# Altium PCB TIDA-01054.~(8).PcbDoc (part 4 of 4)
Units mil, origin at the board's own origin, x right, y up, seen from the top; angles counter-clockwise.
Board outline 4448 x 3930 mil, 4 copper layers (Layer 1 - Top Layer, Layer 2 - GND, Layer 3 - PWR, Layer 4 - Bottom Layer), stack 59.034 mil thick; 538 components, 285 nets, 1542 pads, 769 vias.

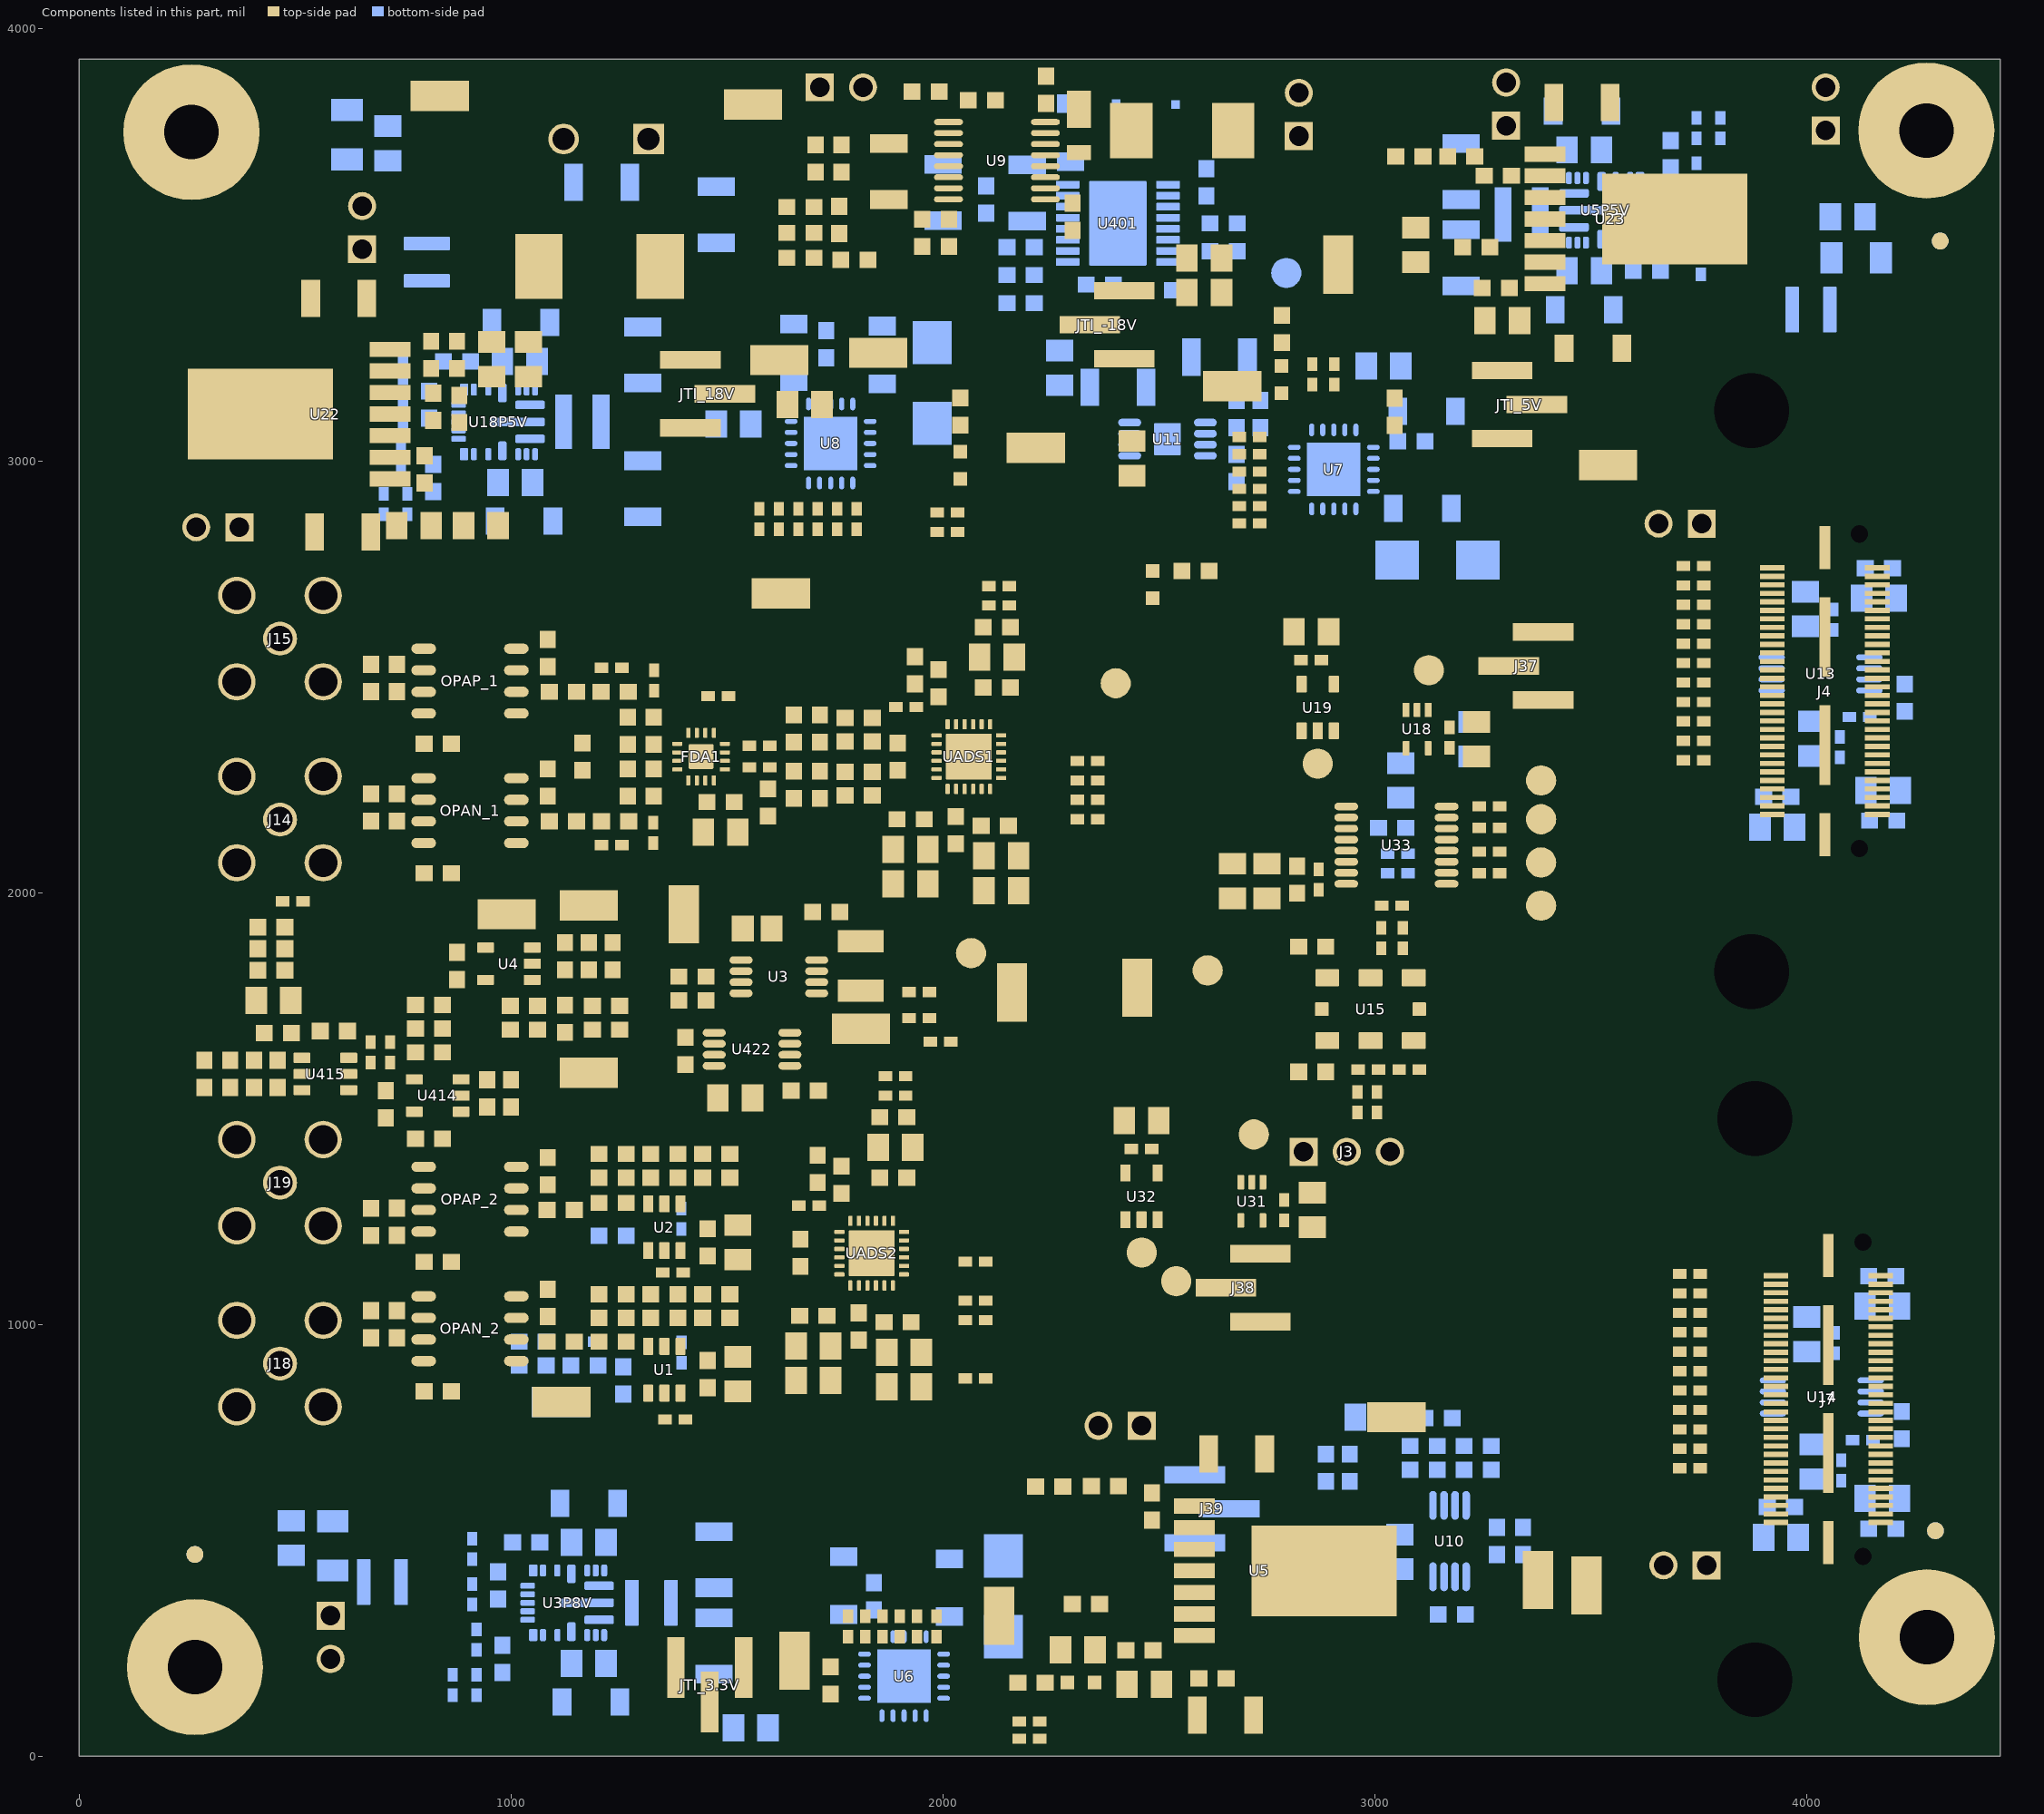
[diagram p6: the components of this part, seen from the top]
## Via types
v1: diameter 20, hole 10, Layer 1 - Top Layer to Layer 4 - Bottom Layer, tented both sides, 381 vias
v2: diameter 20, hole 10, Layer 1 - Top Layer to Layer 4 - Bottom Layer, 258 vias
v3: diameter 20, hole 10, Layer 1 - Top Layer to Layer 4 - Bottom Layer, tented bottom, 57 vias
v4: diameter 19.68, hole 7.87, Layer 1 - Top Layer to Layer 4 - Bottom Layer, tented both sides, 48 vias
v5: diameter 20, hole 10, Layer 1 - Top Layer to Layer 4 - Bottom Layer, tented top, 19 vias
v6: diameter 19.68, hole 7.87, Layer 1 - Top Layer to Layer 4 - Bottom Layer, 6 vias

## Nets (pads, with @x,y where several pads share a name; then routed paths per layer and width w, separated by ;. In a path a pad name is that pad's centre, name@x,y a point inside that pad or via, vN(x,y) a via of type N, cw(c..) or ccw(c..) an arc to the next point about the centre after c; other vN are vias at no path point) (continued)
pads on no net: FID1.1 FID2.1 FID3.1 FID4.1 FID5.1 FID6.1 H1.1 H2.1 H3.1 H4.1 H9. H11. H13. H15. J4.2 J4.3 J4.4 J4.5 J4.6 J4.7 J4.8 J4.9 J4.10 J4.11 J4.12 J4.13 J4.14 J4.15 J4.17 J4.19 J4.21 J4.23 J4.25 J4.26 J4.27 J4.29 J4.31 J4.33 J4.35 J4.36 J4.37 J4.39 J4.41 J4.43 J4.45 J4.46 J4.47 J4.48 J4.49 J4.51 J4.52 J4.53 J4.54 J4.55 J4.57 J4.MH1 J4.MH2 J7.2 J7.3 J7.4 J7.5 J7.6 J7.7 J7.8 J7.9 J7.10 J7.11 J7.12 J7.13 J7.14 J7.15 J7.17 J7.19 J7.21 J7.23 J7.25 J7.26 J7.27 J7.29 J7.31 J7.33 J7.35 J7.36 J7.37 J7.39 J7.41 J7.43 J7.45 J7.46 J7.47 J7.48 J7.49 J7.51 J7.52 J7.53 J7.54 J7.55 J7.57 J7.MH1 J7.MH2 OPAN_1.1 OPAN_1.5 OPAN_1.8 OPAN_2.1 OPAN_2.5 OPAN_2.8 OPAP_1.1 OPAP_1.5 OPAP_1.8 OPAP_2.1 OPAP_2.5 OPAP_2.8 U3P8V.3 U3P8V.4A U3P8V.4B U3P8V.8A U3P8V.8B U3P8V.9A U3P8V.9B U3P8V.9C U3P8V.9D U3P8V.10A U3P8V.10B U3P8V.14A U3P8V.14B U5P5V.3 U5P5V.4A U5P5V.4B U5P5V.8A U5P5V.8B U5P5V.9A U5P5V.9B U5P5V.9C U5P5V.9D U5P5V.10A U5P5V.10B U5P5V.14A U5P5V.14B U9.2 U9.4 U11.3 U11.7 U15.1@2874.25,1656.91 U15.1@2905.75,1656.91 U15.2@2974.25,1656.91 U15.2@3005.75,1656.91 U15.3@3074.25,1656.91 U15.3@3105.75,1656.91 U15.4@3074.25,1802.58 U15.4@3105.75,1802.58 U15.5@2974.25,1802.58 U15.5@3005.75,1802.58 U15.6@2874.25,1802.58 U15.6@2905.75,1802.58 U18P5V.3 U18P5V.4A U18P5V.4B U18P5V.8A U18P5V.8B U18P5V.9A U18P5V.9B U18P5V.9C U18P5V.9D U18P5V.10A U18P5V.10B U18P5V.14A U18P5V.14B U19.1 U32.1 U33.8 U401.17@2405,3550 U422.1 U422.3 U422.5 U422.7 U422.8 UADS1.6 UADS2.6

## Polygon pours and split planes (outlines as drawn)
-18V on Layer 3 - PWR "-18V_L03_P203" (solid, remove dead copper, pour order 203): 263,1101 263,843 330,776 1393,776 1393,1555 1207,1741 928,1741 883,1786 883,1821 933,1871 1376.37,1871 1413,1907.63 1413,2427.79 1569.48,2427.79 1593,2451.31 1593,2501 1628,2536 1908,2536 1908,2735 1437,2735 1258,2556 1258,2552.65 1258,2236 1203,2181 903,2181 863,2221 863,2336 838,2361 458,2361 458,2146 458,1550.99 1153.01,1550.99 1262.75,1441.25 1262.75,1032.25 1261.5,1031 1211.5,981 1204.38,981 898,981 853,1026 853,1136 768,1221 433.18,1221 433.18,1101
5V on Layer 3 - PWR "5V_L03_P202" (solid, remove dead copper, pour order 202): 2212,2712.56 1941.26,2712.56 1941.26,2509.09 1656.26,2509.09 1626.26,2479.09 1626.26,2435.09 1591.26,2400.09 1333,2400.09 1333,1842.56 946.26,1842.57 916.26,1812.57 916.26,1807.56 916.26,1783.88 946.26,1753.88 1181.12,1753.88 1413,1522 1413,776 1981.26,776 1981.26,991.93 1852,1035 1852,1276.59 1981.25,1322.02 1981.25,1483.25 2028,1530 2212,1530 2212,2168 2072,2168 2072,2432.98 2212,2470.38
+18V on Layer 3 - PWR "+18V_L03_P204" (solid, remove dead copper, pour order 204): 1188,2726 1233,2681 1233,2245.04 1188.96,2201 913.62,2201 883,2231.62 883,2346 848,2381 716.39,2381 681.39,2346 433,2346 433,1531 1144.5,1531 1243,1432.5 1243,1276 1203,1236 1203,1181 1243,1141 1243,1045.98 1198.02,1001 913,1001 873,1041 873,1156 793,1236 630.01,1236 630.01,1121 573.12,1121 573.12,1236 413,1236 413,1111 263,1111 263,2726
3.3V on Layer 3 - PWR "3.3V_L03_P206" (solid, remove dead copper, pour order 206): 1698,621 2058,621 2058,1456 2298,1456 2298,1754 2298,2801 2543,3046 3471.66,3046 4273,3046 4273,771 4273,296 3158,296 3003,296 2803,296 2401,296 2227.46,122.46 1698,122.46
AGND on Layer 2 - GND "AGND_L02_P200" (solid, remove dead copper, pour order 200): 229,867 326,770 610,770 1996,770 1996,995.69 1862,1043.69 1862,1112 1896.22,1112 1896.22,1214.6 1862,1214.6 1862,1269 1996,1316.2 1996,1478 2037,1519 2223,1519 2223,2093.44 2223,2181.69 2081,2181.69 2081,2267 2125,2267 2125,2359 2081,2359 2081,2426 2223,2465.25 2223,2532.25 2223,2745 510.02,2745 375.02,2880 229,2880 229,2485
GND on Layer 2 - GND "GND_L02_P201" (solid, remove dead copper, pour order 201): 17,2924 388,2924 522.05,2789.96 2268,2790.95 2268,2431.04 2159,2400.32 2159,2227 2268,2227 2268,1474 2057,1474 2046,1463 2046,1284.45 1935,1243 1935,1070 2046,1025.55 2046,725 542,725 306,489 17,489 17,8.95 4427,9.01 4427,3919 17,3919
AGND on Layer 1 - Top Layer "AGND_L01_P249" (solid, remove dead copper, pour order 249): 454.83,1938.3 454.83,1799.75 534.83,1799.75 534.83,1620.06 535.88,1619.02 579.83,1619.02 579.83,1938.3
GND on Layer 1 - Top Layer "GND_L01_P195" (solid, pour order 195): 2927,3278 2927,3208 2840,3208 2840,3278
GND on Layer 1 - Top Layer "GND_L01_P194" (solid, pour order 194): 2095,2990 2020,2990 2020,2815 2095,2815
+24VDC_IN on Layer 1 - Top Layer "+24VDC_IN_L01_P190" (solid, pour order 190): 755,3355 755,3890 985,3890 1172.5,3890 1172.5,3355
GND on Layer 1 - Top Layer "GND_L01_P193" (solid, pour order 193): 1640,3870 1245,3870 1245,3622.89 1640,3622.89 1640,3647.89 1787.27,3647.89 1787.27,3690 1640,3690
GND on Layer 1 - Top Layer "GND_L01_P196" (solid, pour order 196): 2705,3115 2615,3115 2615,2840 2705,2840 2705,3080
GND on Layer 1 - Top Layer "GND_L01_P197" (solid, pour order 197): 2005,305 2003.9,306.1 1385,306.1 1385,395 1722.6,395 1769.6,348 2005.5,348
GND on Layer 1 - Top Layer "GND_L01_P198" (solid, pour order 198): 2205,18.35 2246.85,18.35 2248,19.5 2248,125 2230,125 2205,100
GND on Layer 1 - Top Layer "GND_L01_P199" (solid, pour order 199): 1820,2870 1820,2810 1440,2810 1440,2870
-0.2V on Layer 1 - Top Layer "-0.2V_L01_P192" (solid, pour order 192): 2870,828.39 3031.52,828.39 3031.52,738.39 2870,738.39
NetC381_1 on Layer 4 - Bottom Layer "NETC381_1_L04_P228" (solid, remove dead copper, pour order 228): 995.2,3030 939.96,3030 939.96,2830 994.95,2830
GND on Layer 4 - Bottom Layer "GND_L04_P245" (solid, remove dead copper, pour order 245): 783.06,60.01 1085.25,60.3 1085.25,278.23 1015,278.23 1015,270.49 955,270.49 875,270.49 875,530 783.06,530
GND on Layer 4 - Bottom Layer "GND_L04_P240" (solid, remove dead copper, pour order 240): 3500,3550 3500,3480 3482.5,3480 3482.5,3290 2915,3290 2915,3890 3490,3890 3490,3610 3280,3610 3280,3550 3403.54,3550
GND on Layer 4 - Bottom Layer "GND_L04_P239" (solid, remove dead copper, pour order 239): 3585,3619.37 3585,3855 3905,3855 3905,3405 3790,3405 3790,3660 3815,3660 3815,3810 3723.35,3810 3723.35,3775 3650,3775 3650,3619.37
NetC369_1 on Layer 4 - Bottom Layer "NETC369_1_L04_P224" (solid, pour order 224): 3995,3920 3495,3920 3495,3695 3580,3695 3580,3860 3905,3860 3905,3400 3585,3400 3585,3480 3490,3480 3490,3290 3995,3290
GND on Layer 4 - Bottom Layer "GND_L04_P236" (solid, pour order 236): 2175,474.98 2175,513 2628.02,513 2628.02,474.98
5.5V on Layer 4 - Bottom Layer "5.5V_L04_P212" (solid, pour order 212): 2945,3090 2945,3060 2985,3020 3075,3020 3075,3152.4 3072.4,3155 2945,3155
5V on Layer 4 - Bottom Layer "5V_L04_P211" (solid, pour order 211): 2980,2935 3070,2935 3070,2850 3105,2815 3105,2715 2970,2715 2895,2715 2895,2905 2915,2905 2915,2865 2945,2865 2945,2905 2975,2935
GND on Layer 4 - Bottom Layer "GND_L04_P233" (solid, pour order 233): 2840,3010 2840,2945 2840,2920 2970,2920 2970,2945 3140,2945 3145,2940 3150,2935 3150,2780 3150,2750 3188,2712 3298.54,2712 3298.54,3091.46 3220,3170 3150,3170 3150,3063.68 3095,3063.68 3095,3010 2970,3010 2970,3040 2840,3040
+24VDC on Layer 4 - Bottom Layer "+24VDC_L04_P216" (solid, pour order 216): 1280,3560 1525,3560 1525,3310 1315,3310 1310,3315 1280,3345 1280,3505
18.5V on Layer 4 - Bottom Layer "18.5V_L04_P214" (solid, pour order 214): 1535,3025 1535,3255 1695,3255 1695,3262.5 1750,3262.5 1750,3220 1735,3205 1710,3205 1695,3190 1695,3150 1695,3115 1675,3115 1665,3105 1665,3085 1600,3085 1600,3025
GND on Layer 4 - Bottom Layer "GND_L04_P232" (solid, pour order 232): 1705,2980 1775,2980 1800,2980 1800,3100 1775,3100 1775,3160 1775,3170 1800,3195 1800,3255 2050,3255 2050,3365 1707.6,3365 1667.6,3325 1622.6,3325 1622.6,3280 1765,3280 1765,3210 1735,3180 1705,3180 1705,3100 1682.21,3100 1682.21,2980
+18V on Layer 4 - Bottom Layer "+18V_L04_P213" (solid, pour order 213): 1785,3115 1785,3155 1820,3190 2025,3190 2025,3035 1815,3035 1815,3050 1855,3050 1855,3080 1820,3080 1815,3085
GND on Layer 4 - Bottom Layer "GND_L04_P234" (solid, pour order 234): 1875,120 1945,120 1970,120 1970,250 1945,250 1945,425 1955,435 2061.26,435 2070,435 2095,410 2190,410 2190,535 1720,535 1720,430.43 1809.37,430.43 1809.37,390.63 1820,380 1858.7,380 1875,380 1875,245 1852.21,245 1852.21,120
3.8V on Layer 4 - Bottom Layer "3.8V_L04_P210" (solid, pour order 210): 1570,25 1735,25 1780,70 1780,180 1780,230 1825,230 1855,260 1855,270 1865,280 1868.54,283.54 1868.54,360 1731.06,360 1730.63,359.57 1715,343.94 1715,180 1715,176 1644,105 1570,105
3.3V on Layer 4 - Bottom Layer "3.3V_L04_P208" (solid, pour order 208): 1955,350 2065,350 2085,330 2190,330 2190,186.65 2178.35,175 2025,175 2025,195 2025,225 2020,230 1985,230 1985,250 1975,260 1955,260 1955,315
GND on Layer 4 - Bottom Layer "GND_L04_P230" (solid, pour order 230): 3103.02,736.68 3013.02,736.68 3013.02,660 2859.52,660 2859.52,579.5 2858.02,578 3013.02,578 3028.02,593 3103.02,593 3118.02,578 3118.02,548 3143.02,548 3143.02,618 3103.02,618
NetC357_1 on Layer 4 - Bottom Layer "NETC357_1_L04_P223" (solid, pour order 223): 705,615 1170,615 1170,575 1170,460 1106,460 1106,530 785,530 785,58 1090,58 1090,255 1165,255 1165,15 675,15 675,143.16 705,160
GND on Layer 4 - Bottom Layer "GND_L04_P235" (solid, pour order 235): 690,517 690,627 456,627 447,618 447,517 515,517
GND on Layer 4 - Bottom Layer "GND_L04_P238" (solid, pour order 238): 790,3744.97 560,3745.01 560,3927.8 762.2,3927.8 790,3900
GND on Layer 4 - Bottom Layer "GND_L04_P241" (solid, remove dead copper, pour order 241): 915,2926 915,2970 848.54,2970 848.54,2926 705,2926 705,3315 590,3315 590,2825 915,2825
NetC381_1 on Layer 4 - Bottom Layer "NETC381_1_L04_P225" (solid, remove dead copper, pour order 225): 1010,3170 1010,3440 377.93,3440 377.93,2957.07 505,2830 580,2830 580,3300 860,3300 935,3225 935,3205 935,3170
GND on Layer 4 - Bottom Layer "GND_L04_P243" (solid, remove dead copper, pour order 243): 1005,3050 1225,3050 1225,3105 1090,3105 1010,3105 1010,3400 1020,3410 1590,3410 1590,3180 1590,2940.58 1475,2830 1005,2830 1005,2915
NetC404_2 on Layer 4 - Bottom Layer "NETC404_2_L04_P227" (solid, remove dead copper, pour order 227): 2491.56,3915 2491.56,3751.42 2491.56,3616.78 2488.92,3616.78 2487.82,3615.67 2487.82,3606.78 2560.18,3606.78 2626.21,3606.78 2638.55,3606.78 2638.54,3710 2560.18,3710 2560.18,3782.8 2560.18,3915
GND on Layer 4 - Bottom Layer "GND_L04_P247" (solid, remove dead copper, pour order 247): 2128.54,3590 2130,3591.46 2130,3735 2447.97,3735 2447.97,3910 2075,3910 1940,3775 1940,3675 1940,3590
NetC403_2 on Layer 4 - Bottom Layer "NETC403_2_L04_P226" (solid, remove dead copper, pour order 226): 2485,3724.51 2485,3366.46 2571.46,3366.46 2575,3370 2575,3455 2658.54,3455 2660,3456.46 2660,3575 2725,3575 2710,3560 2710,3310 2200,3310 2200,3465 2105,3465 2105,3390 2105,3375 2370,3375 2370,3445 2335,3445 2335,3610 2145,3610 2146.16,3611.16 2146.16,3724.51
GND on Layer 4 - Bottom Layer "GND_L04_P229" (solid, remove dead copper, pour order 229): 1170,320 1240,320 1240,300 1400,300 1400,415 1240,415 1240,385 1170,385 1170,615 1710,615 1710,190 1625,105 1439.75,108.55 1295,80 1170,80 1170,105

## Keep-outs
Keep-Out Layer:
  text ".Layer_Name" at 57,-1078.49 h60

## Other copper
Layer 1 - Top Layer:
  rectangle net NetC40_2: 2219,3779 2257.6,3847
  rectangle net +18V: 1975,3110 2075,3190
  rectangle net NetC387_2: 1159.96,3025 1385,3150
  rectangle net NetC363_2: 1385,315 1510,395
  rectangle net NetJTI_3.3V_2: 1370,25 1490,120
  rectangle net 3.8V: 1629,240 1762,290
  region net PRE: 2205,3770.85 2205,3722 2272,3722 2279,3729 2279,3738 2441,3738 2441,3829.79 2376.21,3829.79 2293,3913 2291,3911 2217,3911 2217,3862.32 2220.32,3859 2284,3859 2284,3854 2284,3772
  region net GND: 2249.49,3669 2277,3669 2297,3689 2552,3689 2552,3646 2549,3643 2548.1,3643.9 2264.1,3643.9 2249.49,3643.9
  region net GND: 3335,3580 3288,3580 3288,3547 3115,3547 3108.55,3540.55 3146.59,3502.5 3214.48,3502.5 3234.49,3519 3317.54,3519 3335,3536.46
  region net NetC452_1: 439,1943 352,1943 352,1649 351,1648 256,1648 256,1588 261,1583 263,1585 431,1585 431,1638.78 442.22,1650 452,1650 452,1703 439,1716
  region net GND: 1660,3490 1660,3445 1540,3445 1540,3655 1605,3655 1605,3490
  region net NetC403_2: 2350,3260 2350,3210 2560,3210 2575,3225 2575,3345 2445,3345 2430,3330 2430,3260
  region net NetJTI_-18V_2: 2420,3340 2420,3295 2405,3280 2300,3280 2300,3225 2145,3225 2145,3320 2165,3340
  region net 1050_-18V: 2590,3505 2590,3355 2270,3355 2270,3555 2330,3555 2330,3425 2540,3425 2540,3505
  region net GND: 2525,3831 2774,3831 2774,3650 2838,3650 2838,3515 2774,3515 2679,3515 2679,3355 2610,3355 2605,3360 2605,3515 2555,3515 2525,3545
  region net GND: 925,3220 1090,3220 1130,3180 1130,2820 940,2820 940,2885 1030,2885 1030,2990 1030,3161 925,3161
  region net GND: 210,2925.6 386.4,2925.6 520,2792 570,2792 570,2880 527,2880 527,2965 590,2965 590,3085 790,3085 800,3075 843.78,3075 921.89,2996.89 921.89,2928 1035,2928 1035,3221 907.2,3221 907.2,3125.64 590.86,3129.15 585,3135 585,3435 547.5,3465 290,3465 210,3385
  region net 1050_18V: 640,3420 740,3420 740,3295 790,3295 790,3325 1093.18,3325 1123.18,3270 1245,3270 1255,3260 1505,3260 1505,3195 1415,3195 1415,3205 1350,3205 1350,3195 1335,3180 1140,3180 1140,3200 1095,3245 905,3245 895,3255 790,3255 775,3240 640,3240
  region net AGND: 862.87,1539.75 965,1539.75 965,1409.75 925,1409.75 840,1409.75 840,1449.75 925,1449.75 925,1519.75 862.87,1519.75
  region net REFOUT: 1690,1509.75 1690,1719.75 1880,1719.75 1880,1649.75 1755,1649.75 1750,1644.75 1750,1509.75
  region net AGND: 1510,1609.75 1430,1609.75 1415,1624.75 1340,1624.75 1340,1559.75 1410,1489.75 1510,1489.75
  region net 5V: 1433.54,1694.75 1433.54,1639.75 1340,1639.75 1340,1694.75
  region net 5V: 1563,1817.75 1554,1808.75 1511,1808.75 1410,1909.75 1410,2014.75 1563,2014.75
  region net 5V: 1915,1984.75 1845,1984.75 1835,1994.75 1835,2041.75 1845,2051.75 1915,2051.75
  region net 3.3V: 2053.93,291.07 2053.93,177.07 2083.93,147.07 2193.93,147.07 2193.93,291.07
  region net VDDO: 3194,2062.75 3092,2062.75 3075,2079.75 3075,2159.75 3099,2183.75 3194,2183.75 3194,2164.75 3128,2164.75 3115,2151.75 3115,2091.75 3126,2080.75 3194,2080.75
  region net -18.5V: 2125,3072.5 2125,2977.5 2125,2912.5 2260,2912.5 2260,2977.5 2360,2977.5 2360,3072.5
  region net 3.3V: 2732.21,1257.75 2732.21,1222.75 2760.21,1194.75 2900.21,1194.75 2910.21,1204.75 2910.21,1250.75 2903.21,1257.75
  region net GND: 2775.21,1269.75 2900.21,1269.75 2910.21,1279.75 2910.21,1329.75 2900.21,1339.75 2810.21,1339.75 2775.21,1304.75
  region net 3.3V: 2453,1326.3 2453,1516.75 2438.45,1531.3 2391.55,1531.3 2380,1519.75 2380,1356.13 2409.83,1326.3
  region net GND: 2466.83,1393.3 2501.83,1393.3 2529.83,1421.3 2529.83,1521.3 2519.83,1531.3 2480.83,1531.3 2466.83,1517.3
  region net 3.3V: 3114.81,2351.57 3272.81,2351.57 3272.81,2278.57 3257.81,2263.57 3144.81,2263.57 3114.81,2293.57
  region net GND: 2859.81,2525.57 2894.81,2525.57 2922.81,2553.57 2922.81,2656.94 2915,2664.75 2870,2664.75 2859.81,2654.55
  region net 3.3V: 2847.81,2458.57 2847.81,2656.94 2840,2664.75 2780,2664.74 2772.81,2657.55 2772.81,2503.57 2817.81,2458.57
  region net AGND: 1731.37,1808.16 1731.37,1975.16 1596.79,1975.16 1576.79,1955.16 1576.79,1868.16 1636.79,1808.16
  region net NetC5_2: 1863.15,1859.75 1863.15,1881.6 1863.15,1914.75 1817.31,1914.75 1775,1974.75 1740,1974.75 1740,1859.75
  region net NetC5_1: 1680.79,1802.16 1870,1802.16 1870,1734.75 1701.2,1734.75 1680.79,1755.16
  region net AGND: 1403.79,1829.16 1409.79,1823.16 1409.79,1730.16 1355.79,1730.16 1344.79,1741.16 1344.79,1770.16 1344.79,1819.75 1354.2,1829.16
  region net AGND: 1210,1715.01 1170,1715.01 1165,1720.01 1165,1760.01 1150,1775.01 1105,1775.01 1090,1790.01 1090,1811.01 1079,1822.01 1029,1822.01 1029,1847.01 1193,1847.01 1200,1840.01 1200,1790.01 1210,1780.01
  region net 5V: 1380,1179.75 1580,1179.75 1580,1124.75 1380,1124.75
  region net AGND: 1580,1199.75 1435,1199.75 1435,1239.75 1455,1259.75 1570,1259.75 1580,1249.75
  region net +24VDC: 1295,3360 1500,3360 1500,3515 1295,3515
  region net AGND: 1988,902.74 1995,909.75 1995,979.74 1950,1024.74 1914.45,1024.74 1905,1024.74 1905,984.75 1925,964.75 1925,902.74
  region net 5V: 1380,859.75 1395,874.75 1576.87,874.75 1610,901.75 1613.12,835.08 1580,819.75 1380,819.75
  region net AGND: 1580,894.75 1435,894.75 1435,934.75 1455,954.75 1570,954.75 1580,944.75
  region net AGND: 1610,917.75 1610,1014.75 1635,1039.75 1690,1039.75 1690,917.75
  region net 5V: 1610,834.75 1690,834.75 1690,901.75 1610,901.75
  region net NetC119_1: 1780,1102.75 1780,1009.75 1785,1004.75 1795,1004.75 1825,1004.75 1825,1054.75 1811,1068.75 1811,1102.75
  region net 3.3V: 1985,819.74 1925,819.74 1925,886.74 1982.45,886.74 1994.45,874.75 1994.45,829.19
  region net AGND: 1895,1319.75 1945,1319.75 1975,1349.75 1975,1444.75 1895,1444.75
  region net VDD: 2962,2036.75 2726,2036.75 2718,2044.75 2718,2112.75 2788,2182.75 2962,2182.75 2962,2112.75 2898,2112.75 2885,2099.75 2885,2069.75 2900,2054.75 2962,2054.75
  region net GND: 2635.01,2039.75 2635.01,2114.75 2645.01,2124.75 2692.01,2124.75 2702.01,2114.75 2702.01,2039.75
  region net 3.3V: 2635.01,2014.75 2635.01,1944.75 2645.01,1934.75 2775.01,1934.75 2785.01,1944.75 2785.01,2014.75
  region net 5V: 1475,2271.75 1475,2109.75 1465,2099.75 1395,2099.75 1395,2214.75 1405,2224.75 1405,2271.75
  region net AGND: 1495,2229.75 1495,2109.75 1505,2099.75 1580,2099.75 1615,2134.75 1615,2199.75 1570,2199.75 1560,2209.75 1560,2229.75
  region net NetFDA1_13: 1475,2357.75 1475,2469.75 1425,2469.75 1405,2449.75 1405,2357.75
  region net AGND: 1835,2067.75 1835,2164.75 1860,2189.75 1915,2189.75 1915,2067.75
  region net NetC88_2: 2005,2252.75 2005,2159.75 2010,2154.75 2020,2154.75 2050,2154.75 2050,2204.75 2036,2218.75 2036,2252.75
  region net AGND: 2219.45,2052.74 2219.45,2149.74 2194.45,2174.74 2139.45,2174.74 2130,2174.74 2130,2134.75 2150,2114.75 2150,2052.74
  region net 3.3V: 2220,1972.75 2150,1972.75 2150,2036.74 2220,2036.74
  region net AGND: 2135,2454.75 2185,2454.75 2215,2484.75 2215,2579.75 2135,2579.75
  region net GND: 3157.81,2365.54 3272.81,2365.54 3272.81,2485.04 3210,2485.04 3157.81,2432.85
  region net GND: 4045.03,1236.69 4065.03,1236.69 4065.03,1101.69 4095.03,1071.7 4095.03,576.7 4065.03,546.7 4065.03,416.69 4045.03,416.7 4035.03,426.7 4005.03,456.69 4005.03,1196.69 4035.03,1226.69
  region net GND: 2400,2992.5 2475,2992.5 2490,3007.5 2490,3082.5 2500,3092.5 2540,3092.5 2551.07,3081.43 2551.07,3018.57 2574.79,2994.85 2589.79,2979.85 2589.79,2933.5 2400,2933.5
  region net GND: 4036.51,2056.79 4056.51,2056.79 4056.51,2191.78 4087.01,2222.28 4087.01,2716.29 4056.51,2746.78 4056.51,2876.79 4036.51,2876.78 4026.51,2866.78 3996.52,2836.79 3996.52,2096.79 4026.51,2066.79
  region net 5V: 1392.4,840.61 1410,823.01 1410,786.12 1403.62,779.75
  region net 5V: 597.5,1639.75 682.5,1639.75 682.5,1714.75 597.5,1714.75
  region net AGND: 822.5,1754.75 905,1754.75 905,1664.75 822.5,1664.75
  region net GND: 2870,3585 3015,3585 3015,3515 3130,3515 3130,3562.78 3075,3587.22 3075,3725 3020.02,3725 3020.02,3695 2870,3695
  region net 1050_-18V: 1830,3600 1920,3600 1920,3520 2092,3520 2092,3865 2175,3865 2175,3520 2300,3520 2300,3454 1805,3454 1805,3485 1830,3485
  region net NetC31_1: 1675.16,3905.16 1675,3705 1925,3705 1925,3815 1760.02,3815 1760.08,3905.16
  region net NetCin3_1: 2419.84,815 2419.84,690.84 2407,678 2379,678 2379,592 2379,580 2387,580 2524,580 2525,579 2525,561 2656,561 2657,561 2660,563 2660,759 2532,759 2532,763 2532,766 2532,815
  region net 1050_3.3V: 2630,294 2630,217 2611,198 2611,30 2480,30 2480,212 2466,226 2466,263 2503,263 2536,296
  region net GND: 3089,535 2855.7,615 2773,615 2773,757 2699,757 2699,535 2699,474 2674,449 2555,449 2530,449 2365.83,449 2281.76,520 2277.5,586.5 2252,599 2233,599 2233,615 2212.4,615 2197,615 2197,565.88 2235.88,565.88 2237.76,200 2306.76,200 2306.76,353.61 2366.15,413 2535.2,413 2654,413 2654,50 2814,50 3089,325
  region net 1050_3.3V: 1508.67,265 1588.67,265 1588.67,157.84 1683.5,63 1693,63 1832,63 1839.91,50 1964.67,50 1964.67,10 1508.67,10
  region net NetCin2_1: 3465,3875 3465,3685 3335,3685 3275,3685 3275,3640 3210,3640 3210,3829.96 3344.96,3829.96 3390,3875
  region net 1050_5V: 3445,3430 3290,3430 3290,3370 3300,3360 3300,3275 3270,3275 3225,3230 3225,3185 3455,3185 3460,3190 3460,3315 3445,3330
  region net GND: 3890,3665 3890,3740 3857.34,3740 3857.34,3665 3639.69,3665 3639.33,3664.65 3595,3708.98 3595,3875 3484.67,3875 3485.39,3580 3335,3580 3335,3540 3484.67,3540 3484.67,3220 3520.63,3220 3595,3220 3595,3385 3665,3455 3857.34,3455 3857.34,3414.69 3890,3414.69
  region net NetJTI_5V_2: 3445,3095 3155,3095 3155,3185 3035,3185 3035,3275 3040,3280 3185,3280 3210,3255 3210,3180 3220,3170 3445,3170
  region net NetC374_2: 3210,3085 3210,3015 3215,3010 3435,3010 3465,3040 3695,3040 3695,3205 3470,3205 3470,3180 3460,3170 3460,3085
  region net NetC363_2: 1355,395 1355,135 1410,135 1410,395
  region net NetJTI_18V_2: 1565,3175 1420,3175 1420,3105 1495,3105 1495,3050 1565,3050 1565,3105
  region net 18.5V: 1553,3278 1548,3273 1548,3195.46 1703.46,3195.46 1711,3203 1711,3265.5 1698.5,3278
  region net NetCin1_1: 670,2980 665.8,2980 665.8,3055 596.03,3055 596.03,2933.55 665.8,2933.55 675,2924.35 675,2906.74 650,2881.74 650,2790 765,2790 765,2915 820,2915 820,2980
  text ".Layer_Name" at 57,-1078.49 h60
Layer 2 - GND:
  pour cut-out: 205.85,2897.37 410,2897.37 410,2894.99 480,2824.99 480,2780 212.11,2780 205,2787.11
  text ".Layer_Name" at 57,-1078.49 h60
Layer 3 - PWR:
  rectangle net +24VDC: 1390,3365 1493,3535
  rectangle net +18V: 1925,3115 2025,3190
  region net NetC387_2: 1385,3140 1225,3140 1225,3035 1385,3035
  rectangle net NetC374_2: 3130,3515 3285,3620
  rectangle net NetC381_1: 509,2880 579,2966
  rectangle net NetC401_1: 2617,3676 2886,3795
  rectangle net NetC374_2: 3495,3075 3685,3205
  rectangle net 1050_3.3V: 1790,0 2624,50
  rectangle net 1050_3.3V: 1975,45 2624,96
  rectangle net NetCin1_1: 330,2795 410,2870
  region net GND: 1265,3625 1435,3625 1470,3660 1470,3740 1435,3775 1265,3775
  text ".Layer_Name" at 57,-1078.49 h60
Layer 4 - Bottom Layer:
  rectangle net GND: 3585.29,3637 3637,3657.8
  rectangle net NetC367_1: 4010,3285 4090,3810.08
  rectangle net GND: 690,3025 729.5,3090
  rectangle net GND: 3760,3575 3800,3635
  rectangle net GND: 865,295 895,355
  rectangle net GND: 3415,3610 3434.61,3620
  rectangle net GND: 3585,3636.75 3603,3727.21
  rectangle net GND: 1061,214 1081,328
  rectangle net GND: 902,2825 920,2969.61
  region net NetC403_2: 2475,3655 2335,3655 2335,3450 2475,3450
  rectangle net NetJTI_5V_2: 3035,3185 3160,3275
  rectangle net NetC357_1: 1120,400 1155,505
  rectangle net NetC363_2: 1355,295 1528.31,415
  rectangle net NetC357_1: 1095,210 1155,315
  region net NetC374_2: 3320,3635 3145,3635 3145,3505 3320,3505
  region net NetC369_1: 3570,3700 3505,3700 3505,3620 3570,3620
  region net NetC369_1: 3545,3535 3510,3535 3510,3445 3545,3445
  rectangle net NetC387_2: 1154.96,3020 1345,3145
  rectangle net NetC381_1: 965,3115 995,3205
  rectangle net NetC381_1: 940,2890 995,3030
  rectangle net NetC387_2: 1205,2955 1315,3030
  rectangle net NetC387_2: 1235,3125 1340,3185
  rectangle net NetJTI_18V_2: 1445,3040 1520,3140
  region net GND: 3004,484 3004,583 3000,587 2955,587 2955,486.52 2957.52,484
  region net -0.2V: 2985,825 2865,825 2661.88,680 2510,680 2510,625 2730,625 2865,680 2985,680
  region net GND: 4105,3611.19 4105,3290 4200,3290 4215,3305 4210,3580 4160,3600
  region net GND: 880,3030 905,3030 905,3050 925,3050 925,3000 880,3000
  region net 5V: 910,1773.98 910,1829.75 985,1829.75 985,1773.98
  region net -18V: 2635,3110 2763.54,3110 2763.54,3227.46 2763.54,3295.12 2610,3295.12 2610,3145 2578.96,3145 2578.96,3082.29 2635,3082.29
  region net GND: 2416,3136 2416,3127.95 2470,3127.95 2470,2925 2708.54,2925 2708.54,2978.54 2640,2978.54 2640,3020 2560,3020 2560,3155 2600,3155 2600,3234 2600,3285.12 2565.12,3285.12 2540.12,3285.12 2540.12,3230 2467.5,3230 2455,3215 2416,3215
  region net GND: 728.35,3105 781.46,3105 791.46,3115 830,3115 830,3080 765,3015 723.07,3015 723.07,3105
  region net GND: 3675.41,3560.39 3728.19,3560.39 3728.58,3560 3770,3560 3770,3655 3735,3655 3675.26,3575.29
  region net NetC401_1: 2315,3532.87 2120.02,3532.87 2120.02,3380 2011.1,3380 1935,3485 1935,3590 1937.72,3592.72 2315,3592.72
  region net NetC385_2: 950,3099.94 1069.57,3100.09 1092.94,3123.46 1135,3123.46 1135,3060 1090.5,3060 1070.5,3080 950,3080
  region net GND: 935,3100 902,3100 902,3050 1078.87,3050 1057.87,3071 935,3071
  region net NetC361_2: 1130,364.92 1249.55,365.08 1269.48,385 1295,385 1295,325 1270.5,325 1250.5,345 1130,345
  region net GND: 1105,363 1061,363 1061,320 1242.59,320 1226.59,336 1222.96,336 1105,336
  region net GND: 3560,3575 3603,3575 3603,3615 3422.41,3615 3438.41,3599 3442.04,3599 3560,3599
  region net NetC373_2: 3555,3570.12 3434.97,3569.97 3425,3560 3365,3560 3365,3600 3425.02,3600 3435.02,3590 3555,3590
  region net GND: 1240,3595 1240,3760 1335,3855 1505,3855 1525,3835 1525,3605 1300,3605 1290,3595
  region net +24VDC_IN: 1185,3760 1160,3785 1015,3785 880,3650 880,3420 1160,3420 1185,3445
  region net 3.3V: 3020,2270.04 3250,2270.04 3260,2280.04 3260,2345.04 3040.3,2345.04 3020,2324.75
  region net VDDO: 3115,2049.75 3095,2029.75 3060,2029.75 3060,2114.75 3050,2124.75 3050,2169.75 3020,2199.75 3020,2244.75 3090,2244.75 3115,2219.75
  region net GND: 3260,2369.75 3260,2474.75 3250,2484.75 3200,2484.75 3190,2474.75 3190,2369.75
  region net AGND: 1210,859.75 1280,859.75 1280,809.75 1210,809.75
  region net AGND: 1153.5,1226.24 1223.5,1226.24 1223.5,1176.24 1153.5,1176.24
  region net NetC33_1: 2945.52,464 3122.02,464 3143.02,443 3143.02,383 2988.02,383 2945.52,425.5
  region net 3.3V: 3021.04,486 3086.04,486 3096.04,496 3096.04,558 3086.04,568 3031.04,568 3021.04,558
  region net GND: 989.51,375 890,375 890,277.13 946.3,277.13 946.3,296.3 989.51,339.51
  pour cut-out: 728.35,3120 705,3120 705,3005.49 705.49,3005 735,3005 735,3120
  pour cut-out: 3766.65,3670 3790,3670 3790,3540 3765.06,3540
  pour cut-out: 899.51,390 875,390 875,270.49 899.51,270.49
  region net -18.5V: 2385,3205 2385,3075 2382.5,3072.5 2360,3072.5 2360,2950 2195,2950 2195,3205
  region net NetJTI_-18V_2: 2145,3295 2145,3225 2437.77,3225 2457.77,3245 2490,3245 2490,3285 2490,3295
  region net NetJTI_3.3V_2: 1508.67,93.5 1478.5,93.5 1425.53,88.68 1405,75 1405,30 1510,30
  region net GND: 2130,3450 2165,3450 2165,3325 2040,3325 2040,3365 2130,3365
  region net NetC379_1: 573.74,3725 765,3725 765,3625 864.02,3525.98 864.02,3480 745,3480 725,3500 685,3540 585,3540 575,3550
  region net NetC355_1: 447,493 681,493 681,289 678,286 509,286 509,344 447,406
  text ".Layer_Name" at 57,-1078.49 h60

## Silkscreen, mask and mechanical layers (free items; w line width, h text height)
Top Overlay:
  lines w10: 1555,999.75 1595,959.75 ; 1580,2574.75 1580,2559.75 1700,2559.75 1700,2574.75 ; 1605,2379.75 1605,2559.75 ; 1765,705 1765,975 ; 1495,570 1495,705 1870,705 1870,570 1495,570
  lines w20: 910,3560 960,3560 ; 935,3535 935,3585 ; 1465.69,3562.89 1515.69,3562.89
  text "+24VDC" at 765,3710 h30
  text "+5.5V" at 2840,3550 h30
  text "JMTO_-18V" at 2165,3380 h20
  text "+18.5V" at 1551.07,3283.29 h30
  text "JZO_5V" at 3160,3241 h20
  text "-18V" at 2600,3230 h30
  text "JZO_18V" at 1205,3223 h20
  text "JPRO_-18V" at 2163,3221 h20
  text "+18V" at 1935,3205 h30
  text "JSO_18V" at 1205,3057 h20
  text "JSO_5V" at 3160,2992 h20
  text "-18.5V" at 2135,2910 h30
  text "SYSCLK0" at 3605,2225 h30
  text "SYSCLK1" at 3605,2125 h30
  text "SYSCLK2" at 3605,2025 h30
  text "5V" at 1600,2009.75 h30
  text "SYSCLK3" at 3605,1925 h30
  text "CONVST" at 2310,1044.75 h30
  text "-0.2V" at 3141,775 h30
  text "3.3V" at 2085,310 h30
  text "JSO_3.3V" at 1392,286 h20 r90
  text "JZO_3.3V" at 1553,283.5 h20 r90
  text "TIDA-01054" at 3243,200 h50
  text "3.8V" at 1638,106 h30
  text ".Layer_Name" at 57,-1078.49 h30
Bottom Overlay:
  text "+18V" at 2160,3125 h30
  text "5V" at 1510,1849.75 h30
  text "3.3V" at 2230,250 h30 r270
  text ".Layer_Name" at 57,-1078.49 h30
Top Paste:
  text ".Layer_Name" at 57,-1078.49 h60
Bottom Paste:
  text ".Layer_Name" at 57,-1078.49 h60
Top Solder:
  text ".Layer_Name" at 57,-1078.49 h60
  text ".Layer_Name" at 57,-1078.49 h60
Bottom Solder:
  text ".Layer_Name" at 57,-1078.49 h60
Drill Guide:
  text ".Layer_Name" at 57,-1078.49 h60
M1 Board Outline:
  lines w10: 0,0 4448,-1 4448,3929 0,3930 0,0
  text ".Layer_Name" at 57,-1078.49 h60
M2 Board Dimensions:
  rectangle: -395,-620 -20,-495
  rectangle: -520,-495 -395,-370
  lines w7: -520,-495 480,-495 ; -395,-620 -395,-370 ; -270,-620 -270,-370 ; -20,-620 -20,-370 ; 230,-620 230,-370 ; -520,-620 -520,-370 480,-370 480,-620 -520,-620
  text ".Layer_Name" at 57,-1078.49 h60
M3 3D STEP Top:
  text ".Layer_Name" at 57,-1078.49 h60
M4 3D STEP Bottom:
  text ".Layer_Name" at 57,-1078.49 h60
M5 Assembly Top:
  lines w10: -812,-1150.17 5788,-1150.17 ; -812,-946.83 5790,-946.83 ; -812,-743.5 -812,-1353.5 3193,-1353.5 5790,-1353.5 5790,-743.5 -811.5,-743.5 -811.5,-1353.5 764,-1353.5 ; 1653,-1353.5 1653,-743.5 ; 2920,-946.83 2920,-743.5 ; 3760,-946.83 3760,-743.5 ; 4382,-1360 4382,-1157.17
  text ".VariantName" at 1064,3366 h60
  text "COMPONENTS MARKED 'DNP' SHOULD NOT BE POPULATED." at 633.5,-538.5 h60
  text "ASSEMBLY VARIANT:" at 633,-654 h60
  text "PCB VIEWED FROM TOP SIDE" at -748.5,-875.67 h60
  text "BOARD #:" at 1728,-875.67 h60
  text ".PRJ_Number" at 2273.5,-875.67 h60
  text "REV:" at 3118,-875.67 h60
  text ".PCB_Rev" at 3409.5,-875.67 h60
  text "SVN REV:" at 3956,-875.67 h60
  text ".VersionControl_RevNumber" at 4462,-875.67 h60
  text "TID #:" at 1728,-1079 h60
  text ".TID" at 2273.5,-1079 h60
  text "PLOT NAME =" at -748.5,-1284.34 h60
  text ".plot_File_Name" at 57,-1284.34 h60
  text "GENERATED    :" at 1730,-1284.34 h60
  text ".Print_Date" at 2599.5,-1284.34 h60
  text ".Print_Time" at 3328.5,-1284.34 h60
  text "TEXAS INSTRUMENTS" at 4593,-1284.34 h60
M6 Assembly Bottom:
  lines w10: -812.5,-947.33 5789.5,-947.33 ; -810.5,-1150.67 5789.5,-1150.67 ; 595.5,-1360.5 595.5,-1157.67 ; 1217.5,-947.33 1217.5,-744 ; 2057.5,-947.33 2057.5,-744 ; 3324.5,-1354 3324.5,-744 ; 4213.5,-1354 5789,-1354 5789,-744 -812.5,-744 -812.5,-1354 1784.5,-1354 5789.5,-1354 5789.5,-744
  text "COMPONENTS MARKED 'DNP' SHOULD NOT BE POPULATED." at 5582,-538 h60
  text ".VariantName" at 4538,-654 h60
  text "ASSEMBLY VARIANT:" at 5577,-654 h60
  text ".VersionControl_RevNumber" at 515.5,-876.17 h60
  text "SVN REV:" at 1021.5,-876.17 h60
  text ".PCB_Rev" at 1568,-876.17 h60
  text "REV:" at 1859.5,-876.17 h60
  text ".PRJ_Number" at 2704,-876.17 h60
  text "BOARD #:" at 3249.5,-876.17 h60
  text "PCB VIEWED FROM BOTTOM SIDE" at 5726,-876.17 h60
  text ".TID" at 2704,-1079.5 h60
  text "TID #:" at 3249.5,-1079.5 h60
  text "TEXAS INSTRUMENTS" at 384.5,-1284.84 h60
  text ".Print_Time" at 1649,-1284.84 h60
  text ".Print_Date" at 2378,-1284.84 h60
  text "GENERATED    :" at 3247.5,-1284.84 h60
  text ".plot_File_Name" at 4920.5,-1284.84 h60
  text "PLOT NAME =" at 5726,-1284.84 h60
M9 Title Sheet:
  drawing of 56 lines, arcs and shapes, not listed
  text "1" at 219.84,7816.5 h70
  text "2" at 2715.5,7816.5 h70
  text "3" at 5204.84,7816.5 h70
  text "4" at 7711.51,7816.5 h70
  text "5" at 10210.5,7816.5 h70
  text "6" at 12715.5,7816.5 h70
  text "A" at -936.5,6673.5 h70
  text "A" at 13863.5,6673.5 h70
  text "B" at -936.5,4293.5 h70
  text "B" at 13863.5,4293.5 h70
  text "C" at -936.5,1918.5 h70
  text "C" at 13863.5,1918.5 h70
  text "PROJECT TITLE:" at 10823.5,57.5 h45
  text ".PRJ_Title" at 10873.5,-75.83 h70
  text "DESIGNED FOR:" at 10823.5,-243.5 h45
  text ".PRJ_Customer" at 10873.5,-383.5 h70
  text "D" at -936.5,-451.5 h70
  text "D" at 13863.5,-451.5 h70
  text "FILE NAME:" at 10823.5,-543.5 h45
  text ".PCB_File_Name_No_Path" at 10873.5,-663.5 h70
  text "Texas Instruments (TI) and/or its licensors do not warrant the accuracy or completeness of this specification" at 5854,-825.34 h45
  text "ENGINEER:" at 10823.5,-833.5 h45
  text "LAYOUT BY:" at 12328.5,-833.5 h45
  text "or any information contained therein. TI and/or its licensors do not warrant that this design will meet" at 5809.01,-938 h45
  text ".PRJ_Engineer" at 10873.5,-988.49 h70
  text "the specifications, will be suitable for your application or fit for any particular purpose, or will operate in" at 5809.01,-1050.67 h45
  text ".Layer_Name" at 57,-1078.49 h60
  text "ALTIUM DESIGNER VERSION:" at 12328.5,-1143.5 h45
  text "an implementation. TI and/or its licensors do not warrant that the design is production worthy. You should" at 5809.01,-1163.33 h45
  text "completely validate and test your design implementation to confirm the system functionality for your application." at 5854,-1276 h45
  text ".print_Scale" at 10873.5,-1276.83 h70
  text ".Application_BuildNumber" at 12379,-1276.83 h70
  text "1" at 219.84,-1483.5 h70
  text "2" at 2715.5,-1483.5 h70
  text "3" at 5204.84,-1483.5 h70
  text "4" at 7711.51,-1483.5 h70
  text "5" at 10210.5,-1483.5 h70
  text "6" at 12715.5,-1483.5 h70
M10 Fab Notes:
  drawing of 173 lines, arcs and shapes, not listed
  text "DESIGN INFORMATION" at 11857.02,5981 h60
  text "MIN. TRACK WIDTH:" at 11212.46,5801 h60
  text "8" at 12308.7,5801 h60
  text "MIL" at 12463.46,5801 h60
  text "MIN. CLEARANCE:" at 11212.46,5669 h60
  text "mm" at 12463.46,5669 h60
  text ".127" at 12200,5665 h60
  text "MIN. VIA PAD SIZE:" at 11212.46,5537 h60
  text "20" at 12278.71,5537 h60
  text "MIL" at 12463.46,5537 h60
  text "0.05mm (2MIL)" at 11907.46,5395.29 h60
  text "MINIMUM ANNULAR RING" at 10883.23,5391 h60
  text "EXTERNAL" at 12615.46,5391 h60
  text "PER" at 11083.23,5273 h60
  text "IPC-D-275 CLASS 2 LEVEL C" at 11303.23,5273 h60
  text "MIL, HOLES" at 12791.46,5160.71 h60
  text "+/-" at 12399,5160 h60
  text "+/-" at 13253,5160 h60
  text "REGISTRATION TOLERANCES:" at 10883.23,5155 h60
  text "METAL" at 12083,5155 h60
  text "5" at 12659.2,5155 h60
  text "3" at 13492.2,5155 h60
  text "MIL" at 13608.46,5155 h60
  text "+/-" at 13253,5042 h60
  text "HOLE SIZE TOLERANCE (UNLESS OTHERWISE SPECIFIED):" at 10883.23,5037 h60
  text "3" at 13492.2,5037 h60
  text "MIL" at 13608.46,5037 h60
  text "MATERIAL:" at 10808.46,4827.54 h60
  text "FR-4 High Tg" at 11794.9,4687.21 h60
  text "FR-408" at 11229.46,4678.64 h60
  text "OTHER" at 12717.46,4678.64 h60
  text "X" at 11640,4675 h60
  text "62 MIL (1.6mm) +/-10%" at 11549.56,4515.92 h60
  text "THICKNESS:" at 10883.23,4511.64 h60
  text "X" at 11421.4,4511.64 h60
  text "OTHER" at 12834.46,4511.64 h60
  text "TOLERANCE:" at 10883.23,4353.64 h60
  text "X" at 11722.53,4353.64 h60
  text "ANSI IPC-6012 TYPE 3 CLASS 2" at 11909.48,4353.64 h60
  text "OTHER +/-" at 11909.46,4197.64 h60
  text "BOW & TWIST:" at 10883.23,4040.64 h60
  text "X" at 11722.53,4040.64 h60
  text "ANSI IPC-6012 TYPE 3 CLASS 2" at 11909.48,4040.64 h60
  text "OTHER +/-" at 11909.46,3882.13 h60
  text "DRILLING:" at 10808.46,3743.64 h60
  text "REFERENCE:" at 10883.23,3626.64 h60
  text "X" at 11531.46,3626.64 h60
  text "AS SHOWN" at 11718.46,3626.64 h60
  text "X" at 12432.46,3626.64 h60
  text "NC_DRILL FILES" at 12569.46,3626.64 h60
  text "PTH COPPER THICKNESS:" at 10883.23,3468.64 h60
  text "X" at 12013.46,3468.64 h60
  text "20-30 um" at 12150.46,3468.64 h60
  text "OTHER" at 12867.46,3468.64 h60
  text "BOARD FINISH:" at 10808.46,3309.64 h60
  text "SILKSCREEN:" at 10963.68,3191.64 h60
  text "X" at 11912.46,3191.64 h60
  text "TOP" at 12038.46,3191.64 h60
  text "X" at 12422.46,3191.64 h60
  text "BOTTOM" at 12549.46,3191.64 h60
  text "SILKSCREEN COLOR:" at 10963.68,3024.64 h60
  text "X" at 11911.42,3024.64 h60
  text "WHITE" at 12038.46,3024.64 h60
  text "OTHER" at 12549.46,3024.64 h60
  text "X" at 12042.42,2865.44 h60
  text "GREEN" at 12169.46,2865.44 h60
  text "OTHER" at 12787.46,2865.44 h60
  text "SOLDER RESIST COLOR:" at 10963.68,2854.64 h60
  text "X" at 12042.42,2695.44 h60
  text "MATTE" at 12169.46,2695.44 h60
  text "SEMI-GLOSS" at 12787,2694.8 h60
  text "IMMERSION GOLD (ENIG)" at 11869.46,2506.92 h60
  text "ENEPIG" at 13207,2503.64 h60
  text "SURFACE FINISH:" at 10808.46,2502.64 h60
  text "X" at 11682.51,2502.64 h60
  text "IMM. TIN/SILVER OR EQUIV" at 11138,2345.64 h60
  text "OTHER" at 12569.46,2345.64 h60
  text "ARRAY/PANEL:" at 10808.46,2166.64 h60
  text "CUT AND TRIM PER M1 BOARD OUTLINE" at 11869.46,2162.35 h60
  text "X" at 11680,2155 h60
  text "N.C. ROUTE" at 11869.46,2010.64 h60
  text "V. SCORE" at 12735.46,2010.64 h60
  text "CERTIFICATION:" at 10808.46,1873.64 h60
  text "MATERIALS AND WORKMANSHIP FOR ALL PCBS" at 11533.46,1873.64 h60
  text "TO MEET OR EXCEED THE REQUIREMENTS OF:" at 11533.46,1775.64 h60
  text "X" at 11159.96,1639.13 h60
  text "ANSI IPC-A-600F CLASS ->" at 11298.96,1639.13 h60
  text "X" at 12938.02,1639.13 h60
  text "2" at 13056.96,1639.14 h60
  text "1" at 12741.96,1637.64 h60
  text "3" at 13410.96,1637.64 h60
  text "X" at 11974.02,1479.64 h60
  text "RoHS" at 12110.96,1479.64 h60
  text "OTHER" at 12755.36,1479.64 h60
  text "PER ORDER" at 13152.42,1479.64 h60
  text "ALL BOARDS MUST MEET OR EXCEED UL94-V0 REQUIREMENTS." at 10836,1314 h60
  text "PCB MUST BEAR THE UL94V-0 UL REGISTERED MATERIAL ID NUMBER" at 10836,1194 h60
  text "ADDITIONAL REQUIREMENTS:" at 10808.46,1020.64 h60
  text "MICROSECTION:" at 10883.23,905.64 h60
  text "YES" at 11788.96,905.64 h60
  text "REQUIRED" at 12650.46,749.49 h60
  text "BARE BOARD ELEC. TEST:" at 10883.23,746.64 h60
  text "NONE" at 12188.96,746.64 h60
  text "X" at 12523.46,746.64 h60
  text "PER ORDER" at 13242.46,746.64 h60
  text ".Layer_Name" at 57,-1078.49 h60
M11 Gerber Information:
  lines w10: -812,-1150.17 5788,-1150.17 ; -812,-946.83 5790,-946.83 ; -812,-743.5 -812,-1353.5 3193,-1353.5 5790,-1353.5 5790,-743.5 -811.5,-743.5 -811.5,-1353.5 764,-1353.5 ; 1653,-1353.5 1653,-743.5 ; 2920,-946.83 2920,-743.5 ; 3760,-946.83 3760,-743.5 ; 4382,-1360 4382,-1157.17
  text "ALL ARTWORK VIEWED FROM TOP SIDE" at -748.5,-875.67 h60
  text "BOARD #:" at 1728,-875.67 h60
  text ".PRJ_Number" at 2273.5,-875.67 h60
  text "REV:" at 3118,-875.67 h60
  text ".PCB_Rev" at 3409.5,-875.67 h60
  text "SVN REV:" at 3956,-875.67 h60
  text ".VersionControl_RevNumber" at 4462,-875.67 h60
  text "LAYER NAME =" at -748.5,-1078.49 h60
  text "TID #:" at 1728,-1079 h60
  text ".TID" at 2273.5,-1079 h60
  text "PLOT NAME =" at -748.5,-1284.34 h60
  text ".plot_File_Name" at 57,-1284.34 h60
  text "GENERATED    :" at 1730,-1284.34 h60
  text ".Print_Date" at 2599.5,-1284.34 h60
  text ".Print_Time" at 3328.5,-1284.34 h60
  text "TEXAS INSTRUMENTS" at 4593,-1284.34 h60
M12 Stackup:
  drawing of 295 lines, arcs and shapes, not listed
  text "Layer" at 8787.5,7612.5 h60
  text "Name" at 9197.41,7612.5 h60
  text "Material" at 10607,7612.5 h60
  text "Thickness" at 11466.77,7612.5 h60
  text "Constant" at 12116.6,7612.5 h60
  text "Board Layer Stack" at 12686.47,7612.5 h60
  text "1" at 8787.5,7492.5 h60
  text "Top Overlay" at 9197.41,7492.5 h60
  text "2" at 8787.5,7372.5 h60
  text "Top Solder" at 9197.41,7372.5 h60
  text "Solder Resist" at 10607,7372.5 h60
  text "0.40mil" at 11466.77,7372.5 h60
  text "3.5" at 12116.6,7372.5 h60
  text "3" at 8787.5,7252.5 h60
  text "Layer 1 - Top Layer" at 9197.41,7252.5 h60
  text "Copper" at 10607,7252.5 h60
  text "1.40mil" at 11466.77,7252.5 h60
  text "4" at 8787.5,7132.5 h60
  text "Dielectric 1" at 9197.41,7132.5 h60
  text "370HR" at 10607,7132.5 h60
  text "5.20mil" at 11466.77,7132.5 h60
  text "4.2" at 12116.6,7132.5 h60
  text "5" at 8787.5,7012.5 h60
  text "Layer 2 - GND" at 9197.41,7012.5 h60
  text "Copper" at 10607,7012.5 h60
  text "1.42mil" at 11466.77,7012.5 h60
  text "6" at 8787.5,6892.5 h60
  text "Dielectric 2" at 9197.41,6892.5 h60
  text "370HR" at 10607,6892.5 h60
  text "43.00mil" at 11466.77,6892.5 h60
  text "4.2" at 12116.6,6892.5 h60
  text "7" at 8787.5,6772.5 h60
  text "Layer 3 - PWR" at 9197.41,6772.5 h60
  text "Copper" at 10607,6772.5 h60
  text "1.42mil" at 11466.77,6772.5 h60
  text "8" at 8787.5,6652.5 h60
  text "Dielectric 3" at 9197.41,6652.5 h60
  text "370HR" at 10607,6652.5 h60
  text "5.20mil" at 11466.77,6652.5 h60
  text "4.2" at 12116.6,6652.5 h60
  text "9" at 8787.5,6532.5 h60
  text "Layer 4 - Bottom Layer" at 9197.41,6532.5 h60
  text "Copper" at 10607,6532.5 h60
  text "1.40mil" at 11466.77,6532.5 h60
  text "10" at 8787.5,6412.5 h60
  text "Bottom Solder" at 9197.41,6412.5 h60
  text "Solder Resist" at 10607,6412.5 h60
  text "0.40mil" at 11466.77,6412.5 h60
  text "3.5" at 12116.6,6412.5 h60
  text "11" at 8787.5,6292.5 h60
  text "Bottom Overlay" at 9197.41,6292.5 h60
  text ".Layer_Name" at 57,-1078.49 h60
M13 Component Bodies Top:
  text ".Layer_Name" at 57,-1078.49 h60
M14 Component Bodies Bottom:
  text ".Layer_Name" at 57,-1078.49 h60
M15 Courtyards Top:
  text ".Layer_Name" at 57,-1078.49 h60
M16 Courtyards Bottom:
  text ".Layer_Name" at 57,-1078.49 h60
Drill Drawing:
  circle w10: c6503.72,550.36 r16.58
  circle w10: c6503.72,550.36 r27.63
  circle w10: c6503.72,301.72 r27.63
  lines w10: 6476.09,412.23 6489.9,412.23 6503.72,398.42 6517.53,412.23 6531.34,412.23 6517.53,426.04 6531.34,439.86 6517.53,439.86 6503.72,453.67 6489.9,439.86 6476.09,439.86 6489.9,426.04 6476.09,412.23 ; 6476.09,647.06 6531.34,647.06 6531.34,702.31 6476.09,702.31 6476.09,647.06 ; 6476.09,771.38 6476.09,785.19 6489.9,799 6476.09,812.82 6476.09,826.63 6489.9,826.63 6503.72,812.82 6517.53,826.63 6531.34,826.63 6531.34,812.82 6517.53,799 6531.34,785.19 6531.34,771.38 6517.53,771.38 6503.72,785.19 6489.9,771.38 6476.09,771.38 ; 6476.09,895.7 6531.34,895.7 6531.34,950.95 6476.09,950.95 6476.09,895.7 ; 6476.09,1033.83 6489.9,1033.83 6489.9,1020.02 6517.53,1020.02 6517.53,1033.83 6531.34,1033.83 6531.34,1061.46 6517.53,1061.46 6517.53,1075.27 6489.9,1075.27 6489.9,1061.46 6476.09,1061.46 6476.09,1033.83 ; 6476.09,1171.96 6503.72,1144.34 6531.34,1171.96 6503.72,1199.59 6476.09,1171.96 ; 6476.09,1268.66 6503.72,1282.47 6531.34,1268.66 6517.53,1296.28 6531.34,1323.91 6503.72,1310.1 6476.09,1323.91 6489.9,1296.28 6476.09,1268.66 ; 6487.14,906.75 6520.29,906.75 6520.29,939.9 6487.14,939.9 6487.14,906.75
  lines w12: 6426,236.8 10126.13,236.8 ; 6426,1355.68 10126.13,1355.68 ; 6763.86,112.48 6763.86,1480 ; 7095.86,112.48 7095.86,1480 ; 7732.43,112.48 7732.43,1480 ; 7991.57,112.48 7991.57,1480 ; 8366.72,112.48 8366.72,1480 ; 9559.7,112.48 9559.7,1480 ; 6426,112.48 10126.13,112.48 10126.13,1480 6426,1480 6426,112.48
  text "Symbol" at 6500.59,1392.98 h72
  text "Quantity" at 6801.16,1392.98 h72
  text "Finished Hole Size" at 7133.16,1392.98 h72
  text "Plated" at 7769.72,1392.98 h72
  text "Hole Type" at 8028.86,1392.98 h72
  text "Drill Layer Pair" at 8404.02,1392.98 h72
  text "Hole Tolerance" at 9596.99,1392.98 h72
  text "4" at 6801.16,1268.66 h60
  text "40.00mil (1.016mm)" at 7133.16,1268.66 h60
  text "NPTH" at 7769.72,1268.66 h60
  text "Round" at 8028.86,1268.66 h60
  text "Layer 1 - Top Layer - Layer 4 - Bottom Layer" at 8404.02,1268.66 h60
  text "4" at 6801.16,1144.34 h60
  text "173.23mil (4.400mm)" at 7133.16,1144.34 h60
  text "NPTH" at 7769.72,1144.34 h60
  text "Round" at 8028.86,1144.34 h60
  text "Layer 1 - Top Layer - Layer 4 - Bottom Layer" at 8404.02,1144.34 h60
  text "54" at 6801.16,1020.02 h60
  text "7.87mil (0.200mm)" at 7133.16,1020.02 h60
  text "PTH" at 7769.72,1020.02 h60
  text "Round" at 8028.86,1020.02 h60
  text "Layer 1 - Top Layer - Layer 4 - Bottom Layer" at 8404.02,1020.02 h60
  text "715" at 6801.16,895.7 h60
  text "10.00mil (0.254mm)" at 7133.16,895.7 h60
  text "PTH" at 7769.72,895.7 h60
  text "Round" at 8028.86,895.7 h60
  text "Layer 1 - Top Layer - Layer 4 - Bottom Layer" at 8404.02,895.7 h60
  text "23" at 6801.16,771.38 h60
  text "45.28mil (1.150mm)" at 7133.16,771.38 h60
  text "PTH" at 7769.72,771.38 h60
  text "Round" at 8028.86,771.38 h60
  text "Layer 1 - Top Layer - Layer 4 - Bottom Layer" at 8404.02,771.38 h60
  text "2" at 6801.16,647.06 h60
  text "51.18mil (1.300mm)" at 7133.16,647.06 h60
  text "PTH" at 7769.72,647.06 h60
  text "Round" at 8028.86,647.06 h60
  text "Layer 1 - Top Layer - Layer 4 - Bottom Layer" at 8404.02,647.06 h60
  text "4" at 6801.16,522.74 h60
  text "59.06mil (1.500mm)" at 7133.16,522.74 h60
  text "PTH" at 7769.72,522.74 h60
  text "Round" at 8028.86,522.74 h60
  text "Layer 1 - Top Layer - Layer 4 - Bottom Layer" at 8404.02,522.74 h60
  text "16" at 6801.16,398.42 h60
  text "66.93mil (1.700mm)" at 7133.16,398.42 h60
  text "PTH" at 7769.72,398.42 h60
  text "Round" at 8028.86,398.42 h60
  text "Layer 1 - Top Layer - Layer 4 - Bottom Layer" at 8404.02,398.42 h60
  text "4" at 6801.16,274.1 h60
  text "125.98mil (3.200mm)" at 7133.16,274.1 h60
  text "PTH" at 7769.72,274.1 h60
  text "Round" at 8028.86,274.1 h60
  text "Layer 1 - Top Layer - Layer 4 - Bottom Layer" at 8404.02,274.1 h60
  text "826 Total" at 6801.16,149.78 h60
  text ".Layer_Name" at 57,-1078.49 h60

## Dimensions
0,0 to 0,3930 on M2 Board Dimensions
0,0 to 4448,-1 on M2 Board Dimensions
-520,-620 to 480,-620 on M2 Board Dimensions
